VERSION 5.7 ;
BUSBITCHARS "[]" ;
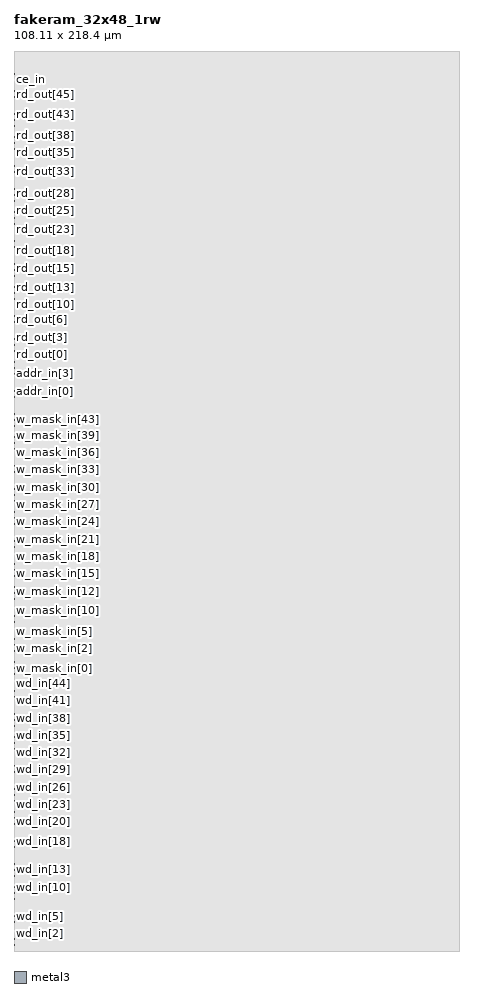
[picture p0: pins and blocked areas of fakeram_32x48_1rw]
MACRO fakeram_32x48_1rw
  FOREIGN fakeram_32x48_1rw 0 0 ;
  SYMMETRY X Y R90 ;
  SIZE 108.110 BY 218.400 ;
  CLASS BLOCK ;
  PIN wd_in[0]
    DIRECTION INPUT ;
    USE SIGNAL ;
    SHAPE ABUTMENT ;
    PORT
      LAYER metal3 ;
      RECT 0.000 1.400 0.140 1.540 ;
    END
  END wd_in[0]
  PIN wd_in[1]
    DIRECTION INPUT ;
    USE SIGNAL ;
    SHAPE ABUTMENT ;
    PORT
      LAYER metal3 ;
      RECT 0.000 2.800 0.140 2.940 ;
    END
  END wd_in[1]
  PIN wd_in[2]
    DIRECTION INPUT ;
    USE SIGNAL ;
    SHAPE ABUTMENT ;
    PORT
      LAYER metal3 ;
      RECT 0.000 4.200 0.140 4.340 ;
    END
  END wd_in[2]
  PIN wd_in[3]
    DIRECTION INPUT ;
    USE SIGNAL ;
    SHAPE ABUTMENT ;
    PORT
      LAYER metal3 ;
      RECT 0.000 5.600 0.140 5.740 ;
    END
  END wd_in[3]
  PIN wd_in[4]
    DIRECTION INPUT ;
    USE SIGNAL ;
    SHAPE ABUTMENT ;
    PORT
      LAYER metal3 ;
      RECT 0.000 7.000 0.140 7.140 ;
    END
  END wd_in[4]
  PIN wd_in[5]
    DIRECTION INPUT ;
    USE SIGNAL ;
    SHAPE ABUTMENT ;
    PORT
      LAYER metal3 ;
      RECT 0.000 8.400 0.140 8.540 ;
    END
  END wd_in[5]
  PIN wd_in[6]
    DIRECTION INPUT ;
    USE SIGNAL ;
    SHAPE ABUTMENT ;
    PORT
      LAYER metal3 ;
      RECT 0.000 9.800 0.140 9.940 ;
    END
  END wd_in[6]
  PIN wd_in[7]
    DIRECTION INPUT ;
    USE SIGNAL ;
    SHAPE ABUTMENT ;
    PORT
      LAYER metal3 ;
      RECT 0.000 11.200 0.140 11.340 ;
    END
  END wd_in[7]
  PIN wd_in[8]
    DIRECTION INPUT ;
    USE SIGNAL ;
    SHAPE ABUTMENT ;
    PORT
      LAYER metal3 ;
      RECT 0.000 12.600 0.140 12.740 ;
    END
  END wd_in[8]
  PIN wd_in[9]
    DIRECTION INPUT ;
    USE SIGNAL ;
    SHAPE ABUTMENT ;
    PORT
      LAYER metal3 ;
      RECT 0.000 14.000 0.140 14.140 ;
    END
  END wd_in[9]
  PIN wd_in[10]
    DIRECTION INPUT ;
    USE SIGNAL ;
    SHAPE ABUTMENT ;
    PORT
      LAYER metal3 ;
      RECT 0.000 15.400 0.140 15.540 ;
    END
  END wd_in[10]
  PIN wd_in[11]
    DIRECTION INPUT ;
    USE SIGNAL ;
    SHAPE ABUTMENT ;
    PORT
      LAYER metal3 ;
      RECT 0.000 16.800 0.140 16.940 ;
    END
  END wd_in[11]
  PIN wd_in[12]
    DIRECTION INPUT ;
    USE SIGNAL ;
    SHAPE ABUTMENT ;
    PORT
      LAYER metal3 ;
      RECT 0.000 18.200 0.140 18.340 ;
    END
  END wd_in[12]
  PIN wd_in[13]
    DIRECTION INPUT ;
    USE SIGNAL ;
    SHAPE ABUTMENT ;
    PORT
      LAYER metal3 ;
      RECT 0.000 19.600 0.140 19.740 ;
    END
  END wd_in[13]
  PIN wd_in[14]
    DIRECTION INPUT ;
    USE SIGNAL ;
    SHAPE ABUTMENT ;
    PORT
      LAYER metal3 ;
      RECT 0.000 21.000 0.140 21.140 ;
    END
  END wd_in[14]
  PIN wd_in[15]
    DIRECTION INPUT ;
    USE SIGNAL ;
    SHAPE ABUTMENT ;
    PORT
      LAYER metal3 ;
      RECT 0.000 22.400 0.140 22.540 ;
    END
  END wd_in[15]
  PIN wd_in[16]
    DIRECTION INPUT ;
    USE SIGNAL ;
    SHAPE ABUTMENT ;
    PORT
      LAYER metal3 ;
      RECT 0.000 23.800 0.140 23.940 ;
    END
  END wd_in[16]
  PIN wd_in[17]
    DIRECTION INPUT ;
    USE SIGNAL ;
    SHAPE ABUTMENT ;
    PORT
      LAYER metal3 ;
      RECT 0.000 25.200 0.140 25.340 ;
    END
  END wd_in[17]
  PIN wd_in[18]
    DIRECTION INPUT ;
    USE SIGNAL ;
    SHAPE ABUTMENT ;
    PORT
      LAYER metal3 ;
      RECT 0.000 26.600 0.140 26.740 ;
    END
  END wd_in[18]
  PIN wd_in[19]
    DIRECTION INPUT ;
    USE SIGNAL ;
    SHAPE ABUTMENT ;
    PORT
      LAYER metal3 ;
      RECT 0.000 28.000 0.140 28.140 ;
    END
  END wd_in[19]
  PIN wd_in[20]
    DIRECTION INPUT ;
    USE SIGNAL ;
    SHAPE ABUTMENT ;
    PORT
      LAYER metal3 ;
      RECT 0.000 29.400 0.140 29.540 ;
    END
  END wd_in[20]
  PIN wd_in[21]
    DIRECTION INPUT ;
    USE SIGNAL ;
    SHAPE ABUTMENT ;
    PORT
      LAYER metal3 ;
      RECT 0.000 30.800 0.140 30.940 ;
    END
  END wd_in[21]
  PIN wd_in[22]
    DIRECTION INPUT ;
    USE SIGNAL ;
    SHAPE ABUTMENT ;
    PORT
      LAYER metal3 ;
      RECT 0.000 32.200 0.140 32.340 ;
    END
  END wd_in[22]
  PIN wd_in[23]
    DIRECTION INPUT ;
    USE SIGNAL ;
    SHAPE ABUTMENT ;
    PORT
      LAYER metal3 ;
      RECT 0.000 33.600 0.140 33.740 ;
    END
  END wd_in[23]
  PIN wd_in[24]
    DIRECTION INPUT ;
    USE SIGNAL ;
    SHAPE ABUTMENT ;
    PORT
      LAYER metal3 ;
      RECT 0.000 35.000 0.140 35.140 ;
    END
  END wd_in[24]
  PIN wd_in[25]
    DIRECTION INPUT ;
    USE SIGNAL ;
    SHAPE ABUTMENT ;
    PORT
      LAYER metal3 ;
      RECT 0.000 36.400 0.140 36.540 ;
    END
  END wd_in[25]
  PIN wd_in[26]
    DIRECTION INPUT ;
    USE SIGNAL ;
    SHAPE ABUTMENT ;
    PORT
      LAYER metal3 ;
      RECT 0.000 37.800 0.140 37.940 ;
    END
  END wd_in[26]
  PIN wd_in[27]
    DIRECTION INPUT ;
    USE SIGNAL ;
    SHAPE ABUTMENT ;
    PORT
      LAYER metal3 ;
      RECT 0.000 39.200 0.140 39.340 ;
    END
  END wd_in[27]
  PIN wd_in[28]
    DIRECTION INPUT ;
    USE SIGNAL ;
    SHAPE ABUTMENT ;
    PORT
      LAYER metal3 ;
      RECT 0.000 40.600 0.140 40.740 ;
    END
  END wd_in[28]
  PIN wd_in[29]
    DIRECTION INPUT ;
    USE SIGNAL ;
    SHAPE ABUTMENT ;
    PORT
      LAYER metal3 ;
      RECT 0.000 42.000 0.140 42.140 ;
    END
  END wd_in[29]
  PIN wd_in[30]
    DIRECTION INPUT ;
    USE SIGNAL ;
    SHAPE ABUTMENT ;
    PORT
      LAYER metal3 ;
      RECT 0.000 43.400 0.140 43.540 ;
    END
  END wd_in[30]
  PIN wd_in[31]
    DIRECTION INPUT ;
    USE SIGNAL ;
    SHAPE ABUTMENT ;
    PORT
      LAYER metal3 ;
      RECT 0.000 44.800 0.140 44.940 ;
    END
  END wd_in[31]
  PIN wd_in[32]
    DIRECTION INPUT ;
    USE SIGNAL ;
    SHAPE ABUTMENT ;
    PORT
      LAYER metal3 ;
      RECT 0.000 46.200 0.140 46.340 ;
    END
  END wd_in[32]
  PIN wd_in[33]
    DIRECTION INPUT ;
    USE SIGNAL ;
    SHAPE ABUTMENT ;
    PORT
      LAYER metal3 ;
      RECT 0.000 47.600 0.140 47.740 ;
    END
  END wd_in[33]
  PIN wd_in[34]
    DIRECTION INPUT ;
    USE SIGNAL ;
    SHAPE ABUTMENT ;
    PORT
      LAYER metal3 ;
      RECT 0.000 49.000 0.140 49.140 ;
    END
  END wd_in[34]
  PIN wd_in[35]
    DIRECTION INPUT ;
    USE SIGNAL ;
    SHAPE ABUTMENT ;
    PORT
      LAYER metal3 ;
      RECT 0.000 50.400 0.140 50.540 ;
    END
  END wd_in[35]
  PIN wd_in[36]
    DIRECTION INPUT ;
    USE SIGNAL ;
    SHAPE ABUTMENT ;
    PORT
      LAYER metal3 ;
      RECT 0.000 51.800 0.140 51.940 ;
    END
  END wd_in[36]
  PIN wd_in[37]
    DIRECTION INPUT ;
    USE SIGNAL ;
    SHAPE ABUTMENT ;
    PORT
      LAYER metal3 ;
      RECT 0.000 53.200 0.140 53.340 ;
    END
  END wd_in[37]
  PIN wd_in[38]
    DIRECTION INPUT ;
    USE SIGNAL ;
    SHAPE ABUTMENT ;
    PORT
      LAYER metal3 ;
      RECT 0.000 54.600 0.140 54.740 ;
    END
  END wd_in[38]
  PIN wd_in[39]
    DIRECTION INPUT ;
    USE SIGNAL ;
    SHAPE ABUTMENT ;
    PORT
      LAYER metal3 ;
      RECT 0.000 56.000 0.140 56.140 ;
    END
  END wd_in[39]
  PIN wd_in[40]
    DIRECTION INPUT ;
    USE SIGNAL ;
    SHAPE ABUTMENT ;
    PORT
      LAYER metal3 ;
      RECT 0.000 57.400 0.140 57.540 ;
    END
  END wd_in[40]
  PIN wd_in[41]
    DIRECTION INPUT ;
    USE SIGNAL ;
    SHAPE ABUTMENT ;
    PORT
      LAYER metal3 ;
      RECT 0.000 58.800 0.140 58.940 ;
    END
  END wd_in[41]
  PIN wd_in[42]
    DIRECTION INPUT ;
    USE SIGNAL ;
    SHAPE ABUTMENT ;
    PORT
      LAYER metal3 ;
      RECT 0.000 60.200 0.140 60.340 ;
    END
  END wd_in[42]
  PIN wd_in[43]
    DIRECTION INPUT ;
    USE SIGNAL ;
    SHAPE ABUTMENT ;
    PORT
      LAYER metal3 ;
      RECT 0.000 61.600 0.140 61.740 ;
    END
  END wd_in[43]
  PIN wd_in[44]
    DIRECTION INPUT ;
    USE SIGNAL ;
    SHAPE ABUTMENT ;
    PORT
      LAYER metal3 ;
      RECT 0.000 63.000 0.140 63.140 ;
    END
  END wd_in[44]
  PIN wd_in[45]
    DIRECTION INPUT ;
    USE SIGNAL ;
    SHAPE ABUTMENT ;
    PORT
      LAYER metal3 ;
      RECT 0.000 64.400 0.140 64.540 ;
    END
  END wd_in[45]
  PIN wd_in[46]
    DIRECTION INPUT ;
    USE SIGNAL ;
    SHAPE ABUTMENT ;
    PORT
      LAYER metal3 ;
      RECT 0.000 65.800 0.140 65.940 ;
    END
  END wd_in[46]
  PIN wd_in[47]
    DIRECTION INPUT ;
    USE SIGNAL ;
    SHAPE ABUTMENT ;
    PORT
      LAYER metal3 ;
      RECT 0.000 67.200 0.140 67.340 ;
    END
  END wd_in[47]
  PIN w_mask_in[0]
    DIRECTION INPUT ;
    USE SIGNAL ;
    SHAPE ABUTMENT ;
    PORT
      LAYER metal3 ;
      RECT 0.000 68.600 0.140 68.740 ;
    END
  END w_mask_in[0]
  PIN w_mask_in[1]
    DIRECTION INPUT ;
    USE SIGNAL ;
    SHAPE ABUTMENT ;
    PORT
      LAYER metal3 ;
      RECT 0.000 70.000 0.140 70.140 ;
    END
  END w_mask_in[1]
  PIN w_mask_in[2]
    DIRECTION INPUT ;
    USE SIGNAL ;
    SHAPE ABUTMENT ;
    PORT
      LAYER metal3 ;
      RECT 0.000 71.400 0.140 71.540 ;
    END
  END w_mask_in[2]
  PIN w_mask_in[3]
    DIRECTION INPUT ;
    USE SIGNAL ;
    SHAPE ABUTMENT ;
    PORT
      LAYER metal3 ;
      RECT 0.000 72.800 0.140 72.940 ;
    END
  END w_mask_in[3]
  PIN w_mask_in[4]
    DIRECTION INPUT ;
    USE SIGNAL ;
    SHAPE ABUTMENT ;
    PORT
      LAYER metal3 ;
      RECT 0.000 74.200 0.140 74.340 ;
    END
  END w_mask_in[4]
  PIN w_mask_in[5]
    DIRECTION INPUT ;
    USE SIGNAL ;
    SHAPE ABUTMENT ;
    PORT
      LAYER metal3 ;
      RECT 0.000 75.600 0.140 75.740 ;
    END
  END w_mask_in[5]
  PIN w_mask_in[6]
    DIRECTION INPUT ;
    USE SIGNAL ;
    SHAPE ABUTMENT ;
    PORT
      LAYER metal3 ;
      RECT 0.000 77.000 0.140 77.140 ;
    END
  END w_mask_in[6]
  PIN w_mask_in[7]
    DIRECTION INPUT ;
    USE SIGNAL ;
    SHAPE ABUTMENT ;
    PORT
      LAYER metal3 ;
      RECT 0.000 78.400 0.140 78.540 ;
    END
  END w_mask_in[7]
  PIN w_mask_in[8]
    DIRECTION INPUT ;
    USE SIGNAL ;
    SHAPE ABUTMENT ;
    PORT
      LAYER metal3 ;
      RECT 0.000 79.800 0.140 79.940 ;
    END
  END w_mask_in[8]
  PIN w_mask_in[9]
    DIRECTION INPUT ;
    USE SIGNAL ;
    SHAPE ABUTMENT ;
    PORT
      LAYER metal3 ;
      RECT 0.000 81.200 0.140 81.340 ;
    END
  END w_mask_in[9]
  PIN w_mask_in[10]
    DIRECTION INPUT ;
    USE SIGNAL ;
    SHAPE ABUTMENT ;
    PORT
      LAYER metal3 ;
      RECT 0.000 82.600 0.140 82.740 ;
    END
  END w_mask_in[10]
  PIN w_mask_in[11]
    DIRECTION INPUT ;
    USE SIGNAL ;
    SHAPE ABUTMENT ;
    PORT
      LAYER metal3 ;
      RECT 0.000 84.000 0.140 84.140 ;
    END
  END w_mask_in[11]
  PIN w_mask_in[12]
    DIRECTION INPUT ;
    USE SIGNAL ;
    SHAPE ABUTMENT ;
    PORT
      LAYER metal3 ;
      RECT 0.000 85.400 0.140 85.540 ;
    END
  END w_mask_in[12]
  PIN w_mask_in[13]
    DIRECTION INPUT ;
    USE SIGNAL ;
    SHAPE ABUTMENT ;
    PORT
      LAYER metal3 ;
      RECT 0.000 86.800 0.140 86.940 ;
    END
  END w_mask_in[13]
  PIN w_mask_in[14]
    DIRECTION INPUT ;
    USE SIGNAL ;
    SHAPE ABUTMENT ;
    PORT
      LAYER metal3 ;
      RECT 0.000 88.200 0.140 88.340 ;
    END
  END w_mask_in[14]
  PIN w_mask_in[15]
    DIRECTION INPUT ;
    USE SIGNAL ;
    SHAPE ABUTMENT ;
    PORT
      LAYER metal3 ;
      RECT 0.000 89.600 0.140 89.740 ;
    END
  END w_mask_in[15]
  PIN w_mask_in[16]
    DIRECTION INPUT ;
    USE SIGNAL ;
    SHAPE ABUTMENT ;
    PORT
      LAYER metal3 ;
      RECT 0.000 91.000 0.140 91.140 ;
    END
  END w_mask_in[16]
  PIN w_mask_in[17]
    DIRECTION INPUT ;
    USE SIGNAL ;
    SHAPE ABUTMENT ;
    PORT
      LAYER metal3 ;
      RECT 0.000 92.400 0.140 92.540 ;
    END
  END w_mask_in[17]
  PIN w_mask_in[18]
    DIRECTION INPUT ;
    USE SIGNAL ;
    SHAPE ABUTMENT ;
    PORT
      LAYER metal3 ;
      RECT 0.000 93.800 0.140 93.940 ;
    END
  END w_mask_in[18]
  PIN w_mask_in[19]
    DIRECTION INPUT ;
    USE SIGNAL ;
    SHAPE ABUTMENT ;
    PORT
      LAYER metal3 ;
      RECT 0.000 95.200 0.140 95.340 ;
    END
  END w_mask_in[19]
  PIN w_mask_in[20]
    DIRECTION INPUT ;
    USE SIGNAL ;
    SHAPE ABUTMENT ;
    PORT
      LAYER metal3 ;
      RECT 0.000 96.600 0.140 96.740 ;
    END
  END w_mask_in[20]
  PIN w_mask_in[21]
    DIRECTION INPUT ;
    USE SIGNAL ;
    SHAPE ABUTMENT ;
    PORT
      LAYER metal3 ;
      RECT 0.000 98.000 0.140 98.140 ;
    END
  END w_mask_in[21]
  PIN w_mask_in[22]
    DIRECTION INPUT ;
    USE SIGNAL ;
    SHAPE ABUTMENT ;
    PORT
      LAYER metal3 ;
      RECT 0.000 99.400 0.140 99.540 ;
    END
  END w_mask_in[22]
  PIN w_mask_in[23]
    DIRECTION INPUT ;
    USE SIGNAL ;
    SHAPE ABUTMENT ;
    PORT
      LAYER metal3 ;
      RECT 0.000 100.800 0.140 100.940 ;
    END
  END w_mask_in[23]
  PIN w_mask_in[24]
    DIRECTION INPUT ;
    USE SIGNAL ;
    SHAPE ABUTMENT ;
    PORT
      LAYER metal3 ;
      RECT 0.000 102.200 0.140 102.340 ;
    END
  END w_mask_in[24]
  PIN w_mask_in[25]
    DIRECTION INPUT ;
    USE SIGNAL ;
    SHAPE ABUTMENT ;
    PORT
      LAYER metal3 ;
      RECT 0.000 103.600 0.140 103.740 ;
    END
  END w_mask_in[25]
  PIN w_mask_in[26]
    DIRECTION INPUT ;
    USE SIGNAL ;
    SHAPE ABUTMENT ;
    PORT
      LAYER metal3 ;
      RECT 0.000 105.000 0.140 105.140 ;
    END
  END w_mask_in[26]
  PIN w_mask_in[27]
    DIRECTION INPUT ;
    USE SIGNAL ;
    SHAPE ABUTMENT ;
    PORT
      LAYER metal3 ;
      RECT 0.000 106.400 0.140 106.540 ;
    END
  END w_mask_in[27]
  PIN w_mask_in[28]
    DIRECTION INPUT ;
    USE SIGNAL ;
    SHAPE ABUTMENT ;
    PORT
      LAYER metal3 ;
      RECT 0.000 107.800 0.140 107.940 ;
    END
  END w_mask_in[28]
  PIN w_mask_in[29]
    DIRECTION INPUT ;
    USE SIGNAL ;
    SHAPE ABUTMENT ;
    PORT
      LAYER metal3 ;
      RECT 0.000 109.200 0.140 109.340 ;
    END
  END w_mask_in[29]
  PIN w_mask_in[30]
    DIRECTION INPUT ;
    USE SIGNAL ;
    SHAPE ABUTMENT ;
    PORT
      LAYER metal3 ;
      RECT 0.000 110.600 0.140 110.740 ;
    END
  END w_mask_in[30]
  PIN w_mask_in[31]
    DIRECTION INPUT ;
    USE SIGNAL ;
    SHAPE ABUTMENT ;
    PORT
      LAYER metal3 ;
      RECT 0.000 112.000 0.140 112.140 ;
    END
  END w_mask_in[31]
  PIN w_mask_in[32]
    DIRECTION INPUT ;
    USE SIGNAL ;
    SHAPE ABUTMENT ;
    PORT
      LAYER metal3 ;
      RECT 0.000 113.400 0.140 113.540 ;
    END
  END w_mask_in[32]
  PIN w_mask_in[33]
    DIRECTION INPUT ;
    USE SIGNAL ;
    SHAPE ABUTMENT ;
    PORT
      LAYER metal3 ;
      RECT 0.000 114.800 0.140 114.940 ;
    END
  END w_mask_in[33]
  PIN w_mask_in[34]
    DIRECTION INPUT ;
    USE SIGNAL ;
    SHAPE ABUTMENT ;
    PORT
      LAYER metal3 ;
      RECT 0.000 116.200 0.140 116.340 ;
    END
  END w_mask_in[34]
  PIN w_mask_in[35]
    DIRECTION INPUT ;
    USE SIGNAL ;
    SHAPE ABUTMENT ;
    PORT
      LAYER metal3 ;
      RECT 0.000 117.600 0.140 117.740 ;
    END
  END w_mask_in[35]
  PIN w_mask_in[36]
    DIRECTION INPUT ;
    USE SIGNAL ;
    SHAPE ABUTMENT ;
    PORT
      LAYER metal3 ;
      RECT 0.000 119.000 0.140 119.140 ;
    END
  END w_mask_in[36]
  PIN w_mask_in[37]
    DIRECTION INPUT ;
    USE SIGNAL ;
    SHAPE ABUTMENT ;
    PORT
      LAYER metal3 ;
      RECT 0.000 120.400 0.140 120.540 ;
    END
  END w_mask_in[37]
  PIN w_mask_in[38]
    DIRECTION INPUT ;
    USE SIGNAL ;
    SHAPE ABUTMENT ;
    PORT
      LAYER metal3 ;
      RECT 0.000 121.800 0.140 121.940 ;
    END
  END w_mask_in[38]
  PIN w_mask_in[39]
    DIRECTION INPUT ;
    USE SIGNAL ;
    SHAPE ABUTMENT ;
    PORT
      LAYER metal3 ;
      RECT 0.000 123.200 0.140 123.340 ;
    END
  END w_mask_in[39]
  PIN w_mask_in[40]
    DIRECTION INPUT ;
    USE SIGNAL ;
    SHAPE ABUTMENT ;
    PORT
      LAYER metal3 ;
      RECT 0.000 124.600 0.140 124.740 ;
    END
  END w_mask_in[40]
  PIN w_mask_in[41]
    DIRECTION INPUT ;
    USE SIGNAL ;
    SHAPE ABUTMENT ;
    PORT
      LAYER metal3 ;
      RECT 0.000 126.000 0.140 126.140 ;
    END
  END w_mask_in[41]
  PIN w_mask_in[42]
    DIRECTION INPUT ;
    USE SIGNAL ;
    SHAPE ABUTMENT ;
    PORT
      LAYER metal3 ;
      RECT 0.000 127.400 0.140 127.540 ;
    END
  END w_mask_in[42]
  PIN w_mask_in[43]
    DIRECTION INPUT ;
    USE SIGNAL ;
    SHAPE ABUTMENT ;
    PORT
      LAYER metal3 ;
      RECT 0.000 128.800 0.140 128.940 ;
    END
  END w_mask_in[43]
  PIN w_mask_in[44]
    DIRECTION INPUT ;
    USE SIGNAL ;
    SHAPE ABUTMENT ;
    PORT
      LAYER metal3 ;
      RECT 0.000 130.200 0.140 130.340 ;
    END
  END w_mask_in[44]
  PIN w_mask_in[45]
    DIRECTION INPUT ;
    USE SIGNAL ;
    SHAPE ABUTMENT ;
    PORT
      LAYER metal3 ;
      RECT 0.000 131.600 0.140 131.740 ;
    END
  END w_mask_in[45]
  PIN w_mask_in[46]
    DIRECTION INPUT ;
    USE SIGNAL ;
    SHAPE ABUTMENT ;
    PORT
      LAYER metal3 ;
      RECT 0.000 133.000 0.140 133.140 ;
    END
  END w_mask_in[46]
  PIN w_mask_in[47]
    DIRECTION INPUT ;
    USE SIGNAL ;
    SHAPE ABUTMENT ;
    PORT
      LAYER metal3 ;
      RECT 0.000 134.400 0.140 134.540 ;
    END
  END w_mask_in[47]
  PIN addr_in[0]
    DIRECTION INPUT ;
    USE SIGNAL ;
    SHAPE ABUTMENT ;
    PORT
      LAYER metal3 ;
      RECT 0.000 135.800 0.140 135.940 ;
    END
  END addr_in[0]
  PIN addr_in[1]
    DIRECTION INPUT ;
    USE SIGNAL ;
    SHAPE ABUTMENT ;
    PORT
      LAYER metal3 ;
      RECT 0.000 137.200 0.140 137.340 ;
    END
  END addr_in[1]
  PIN addr_in[2]
    DIRECTION INPUT ;
    USE SIGNAL ;
    SHAPE ABUTMENT ;
    PORT
      LAYER metal3 ;
      RECT 0.000 138.600 0.140 138.740 ;
    END
  END addr_in[2]
  PIN addr_in[3]
    DIRECTION INPUT ;
    USE SIGNAL ;
    SHAPE ABUTMENT ;
    PORT
      LAYER metal3 ;
      RECT 0.000 140.000 0.140 140.140 ;
    END
  END addr_in[3]
  PIN addr_in[4]
    DIRECTION INPUT ;
    USE SIGNAL ;
    SHAPE ABUTMENT ;
    PORT
      LAYER metal3 ;
      RECT 0.000 141.400 0.140 141.540 ;
    END
  END addr_in[4]
  PIN rd_out[0]
    DIRECTION OUTPUT ;
    USE SIGNAL ;
    SHAPE ABUTMENT ;
    PORT
      LAYER metal3 ;
      RECT 0.000 142.800 0.140 142.940 ;
    END
  END rd_out[0]
  PIN rd_out[1]
    DIRECTION OUTPUT ;
    USE SIGNAL ;
    SHAPE ABUTMENT ;
    PORT
      LAYER metal3 ;
      RECT 0.000 144.200 0.140 144.340 ;
    END
  END rd_out[1]
  PIN rd_out[2]
    DIRECTION OUTPUT ;
    USE SIGNAL ;
    SHAPE ABUTMENT ;
    PORT
      LAYER metal3 ;
      RECT 0.000 145.600 0.140 145.740 ;
    END
  END rd_out[2]
  PIN rd_out[3]
    DIRECTION OUTPUT ;
    USE SIGNAL ;
    SHAPE ABUTMENT ;
    PORT
      LAYER metal3 ;
      RECT 0.000 147.000 0.140 147.140 ;
    END
  END rd_out[3]
  PIN rd_out[4]
    DIRECTION OUTPUT ;
    USE SIGNAL ;
    SHAPE ABUTMENT ;
    PORT
      LAYER metal3 ;
      RECT 0.000 148.400 0.140 148.540 ;
    END
  END rd_out[4]
  PIN rd_out[5]
    DIRECTION OUTPUT ;
    USE SIGNAL ;
    SHAPE ABUTMENT ;
    PORT
      LAYER metal3 ;
      RECT 0.000 149.800 0.140 149.940 ;
    END
  END rd_out[5]
  PIN rd_out[6]
    DIRECTION OUTPUT ;
    USE SIGNAL ;
    SHAPE ABUTMENT ;
    PORT
      LAYER metal3 ;
      RECT 0.000 151.200 0.140 151.340 ;
    END
  END rd_out[6]
  PIN rd_out[7]
    DIRECTION OUTPUT ;
    USE SIGNAL ;
    SHAPE ABUTMENT ;
    PORT
      LAYER metal3 ;
      RECT 0.000 152.600 0.140 152.740 ;
    END
  END rd_out[7]
  PIN rd_out[8]
    DIRECTION OUTPUT ;
    USE SIGNAL ;
    SHAPE ABUTMENT ;
    PORT
      LAYER metal3 ;
      RECT 0.000 154.000 0.140 154.140 ;
    END
  END rd_out[8]
  PIN rd_out[9]
    DIRECTION OUTPUT ;
    USE SIGNAL ;
    SHAPE ABUTMENT ;
    PORT
      LAYER metal3 ;
      RECT 0.000 155.400 0.140 155.540 ;
    END
  END rd_out[9]
  PIN rd_out[10]
    DIRECTION OUTPUT ;
    USE SIGNAL ;
    SHAPE ABUTMENT ;
    PORT
      LAYER metal3 ;
      RECT 0.000 156.800 0.140 156.940 ;
    END
  END rd_out[10]
  PIN rd_out[11]
    DIRECTION OUTPUT ;
    USE SIGNAL ;
    SHAPE ABUTMENT ;
    PORT
      LAYER metal3 ;
      RECT 0.000 158.200 0.140 158.340 ;
    END
  END rd_out[11]
  PIN rd_out[12]
    DIRECTION OUTPUT ;
    USE SIGNAL ;
    SHAPE ABUTMENT ;
    PORT
      LAYER metal3 ;
      RECT 0.000 159.600 0.140 159.740 ;
    END
  END rd_out[12]
  PIN rd_out[13]
    DIRECTION OUTPUT ;
    USE SIGNAL ;
    SHAPE ABUTMENT ;
    PORT
      LAYER metal3 ;
      RECT 0.000 161.000 0.140 161.140 ;
    END
  END rd_out[13]
  PIN rd_out[14]
    DIRECTION OUTPUT ;
    USE SIGNAL ;
    SHAPE ABUTMENT ;
    PORT
      LAYER metal3 ;
      RECT 0.000 162.400 0.140 162.540 ;
    END
  END rd_out[14]
  PIN rd_out[15]
    DIRECTION OUTPUT ;
    USE SIGNAL ;
    SHAPE ABUTMENT ;
    PORT
      LAYER metal3 ;
      RECT 0.000 163.800 0.140 163.940 ;
    END
  END rd_out[15]
  PIN rd_out[16]
    DIRECTION OUTPUT ;
    USE SIGNAL ;
    SHAPE ABUTMENT ;
    PORT
      LAYER metal3 ;
      RECT 0.000 165.200 0.140 165.340 ;
    END
  END rd_out[16]
  PIN rd_out[17]
    DIRECTION OUTPUT ;
    USE SIGNAL ;
    SHAPE ABUTMENT ;
    PORT
      LAYER metal3 ;
      RECT 0.000 166.600 0.140 166.740 ;
    END
  END rd_out[17]
  PIN rd_out[18]
    DIRECTION OUTPUT ;
    USE SIGNAL ;
    SHAPE ABUTMENT ;
    PORT
      LAYER metal3 ;
      RECT 0.000 168.000 0.140 168.140 ;
    END
  END rd_out[18]
  PIN rd_out[19]
    DIRECTION OUTPUT ;
    USE SIGNAL ;
    SHAPE ABUTMENT ;
    PORT
      LAYER metal3 ;
      RECT 0.000 169.400 0.140 169.540 ;
    END
  END rd_out[19]
  PIN rd_out[20]
    DIRECTION OUTPUT ;
    USE SIGNAL ;
    SHAPE ABUTMENT ;
    PORT
      LAYER metal3 ;
      RECT 0.000 170.800 0.140 170.940 ;
    END
  END rd_out[20]
  PIN rd_out[21]
    DIRECTION OUTPUT ;
    USE SIGNAL ;
    SHAPE ABUTMENT ;
    PORT
      LAYER metal3 ;
      RECT 0.000 172.200 0.140 172.340 ;
    END
  END rd_out[21]
  PIN rd_out[22]
    DIRECTION OUTPUT ;
    USE SIGNAL ;
    SHAPE ABUTMENT ;
    PORT
      LAYER metal3 ;
      RECT 0.000 173.600 0.140 173.740 ;
    END
  END rd_out[22]
  PIN rd_out[23]
    DIRECTION OUTPUT ;
    USE SIGNAL ;
    SHAPE ABUTMENT ;
    PORT
      LAYER metal3 ;
      RECT 0.000 175.000 0.140 175.140 ;
    END
  END rd_out[23]
  PIN rd_out[24]
    DIRECTION OUTPUT ;
    USE SIGNAL ;
    SHAPE ABUTMENT ;
    PORT
      LAYER metal3 ;
      RECT 0.000 176.400 0.140 176.540 ;
    END
  END rd_out[24]
  PIN rd_out[25]
    DIRECTION OUTPUT ;
    USE SIGNAL ;
    SHAPE ABUTMENT ;
    PORT
      LAYER metal3 ;
      RECT 0.000 177.800 0.140 177.940 ;
    END
  END rd_out[25]
  PIN rd_out[26]
    DIRECTION OUTPUT ;
    USE SIGNAL ;
    SHAPE ABUTMENT ;
    PORT
      LAYER metal3 ;
      RECT 0.000 179.200 0.140 179.340 ;
    END
  END rd_out[26]
  PIN rd_out[27]
    DIRECTION OUTPUT ;
    USE SIGNAL ;
    SHAPE ABUTMENT ;
    PORT
      LAYER metal3 ;
      RECT 0.000 180.600 0.140 180.740 ;
    END
  END rd_out[27]
  PIN rd_out[28]
    DIRECTION OUTPUT ;
    USE SIGNAL ;
    SHAPE ABUTMENT ;
    PORT
      LAYER metal3 ;
      RECT 0.000 182.000 0.140 182.140 ;
    END
  END rd_out[28]
  PIN rd_out[29]
    DIRECTION OUTPUT ;
    USE SIGNAL ;
    SHAPE ABUTMENT ;
    PORT
      LAYER metal3 ;
      RECT 0.000 183.400 0.140 183.540 ;
    END
  END rd_out[29]
  PIN rd_out[30]
    DIRECTION OUTPUT ;
    USE SIGNAL ;
    SHAPE ABUTMENT ;
    PORT
      LAYER metal3 ;
      RECT 0.000 184.800 0.140 184.940 ;
    END
  END rd_out[30]
  PIN rd_out[31]
    DIRECTION OUTPUT ;
    USE SIGNAL ;
    SHAPE ABUTMENT ;
    PORT
      LAYER metal3 ;
      RECT 0.000 186.200 0.140 186.340 ;
    END
  END rd_out[31]
  PIN rd_out[32]
    DIRECTION OUTPUT ;
    USE SIGNAL ;
    SHAPE ABUTMENT ;
    PORT
      LAYER metal3 ;
      RECT 0.000 187.600 0.140 187.740 ;
    END
  END rd_out[32]
  PIN rd_out[33]
    DIRECTION OUTPUT ;
    USE SIGNAL ;
    SHAPE ABUTMENT ;
    PORT
      LAYER metal3 ;
      RECT 0.000 189.000 0.140 189.140 ;
    END
  END rd_out[33]
  PIN rd_out[34]
    DIRECTION OUTPUT ;
    USE SIGNAL ;
    SHAPE ABUTMENT ;
    PORT
      LAYER metal3 ;
      RECT 0.000 190.400 0.140 190.540 ;
    END
  END rd_out[34]
  PIN rd_out[35]
    DIRECTION OUTPUT ;
    USE SIGNAL ;
    SHAPE ABUTMENT ;
    PORT
      LAYER metal3 ;
      RECT 0.000 191.800 0.140 191.940 ;
    END
  END rd_out[35]
  PIN rd_out[36]
    DIRECTION OUTPUT ;
    USE SIGNAL ;
    SHAPE ABUTMENT ;
    PORT
      LAYER metal3 ;
      RECT 0.000 193.200 0.140 193.340 ;
    END
  END rd_out[36]
  PIN rd_out[37]
    DIRECTION OUTPUT ;
    USE SIGNAL ;
    SHAPE ABUTMENT ;
    PORT
      LAYER metal3 ;
      RECT 0.000 194.600 0.140 194.740 ;
    END
  END rd_out[37]
  PIN rd_out[38]
    DIRECTION OUTPUT ;
    USE SIGNAL ;
    SHAPE ABUTMENT ;
    PORT
      LAYER metal3 ;
      RECT 0.000 196.000 0.140 196.140 ;
    END
  END rd_out[38]
  PIN rd_out[39]
    DIRECTION OUTPUT ;
    USE SIGNAL ;
    SHAPE ABUTMENT ;
    PORT
      LAYER metal3 ;
      RECT 0.000 197.400 0.140 197.540 ;
    END
  END rd_out[39]
  PIN rd_out[40]
    DIRECTION OUTPUT ;
    USE SIGNAL ;
    SHAPE ABUTMENT ;
    PORT
      LAYER metal3 ;
      RECT 0.000 198.800 0.140 198.940 ;
    END
  END rd_out[40]
  PIN rd_out[41]
    DIRECTION OUTPUT ;
    USE SIGNAL ;
    SHAPE ABUTMENT ;
    PORT
      LAYER metal3 ;
      RECT 0.000 200.200 0.140 200.340 ;
    END
  END rd_out[41]
  PIN rd_out[42]
    DIRECTION OUTPUT ;
    USE SIGNAL ;
    SHAPE ABUTMENT ;
    PORT
      LAYER metal3 ;
      RECT 0.000 201.600 0.140 201.740 ;
    END
  END rd_out[42]
  PIN rd_out[43]
    DIRECTION OUTPUT ;
    USE SIGNAL ;
    SHAPE ABUTMENT ;
    PORT
      LAYER metal3 ;
      RECT 0.000 203.000 0.140 203.140 ;
    END
  END rd_out[43]
  PIN rd_out[44]
    DIRECTION OUTPUT ;
    USE SIGNAL ;
    SHAPE ABUTMENT ;
    PORT
      LAYER metal3 ;
      RECT 0.000 204.400 0.140 204.540 ;
    END
  END rd_out[44]
  PIN rd_out[45]
    DIRECTION OUTPUT ;
    USE SIGNAL ;
    SHAPE ABUTMENT ;
    PORT
      LAYER metal3 ;
      RECT 0.000 205.800 0.140 205.940 ;
    END
  END rd_out[45]
  PIN rd_out[46]
    DIRECTION OUTPUT ;
    USE SIGNAL ;
    SHAPE ABUTMENT ;
    PORT
      LAYER metal3 ;
      RECT 0.000 207.200 0.140 207.340 ;
    END
  END rd_out[46]
  PIN rd_out[47]
    DIRECTION OUTPUT ;
    USE SIGNAL ;
    SHAPE ABUTMENT ;
    PORT
      LAYER metal3 ;
      RECT 0.000 208.600 0.140 208.740 ;
    END
  END rd_out[47]
  PIN clk
    DIRECTION INPUT ;
    USE SIGNAL ;
    SHAPE ABUTMENT ;
    PORT
      LAYER metal3 ;
      RECT 0.000 210.000 0.140 210.140 ;
    END
  END clk
  PIN ce_in
    DIRECTION INPUT ;
    USE SIGNAL ;
    SHAPE ABUTMENT ;
    PORT
      LAYER metal3 ;
      RECT 0.000 211.400 0.140 211.540 ;
    END
  END ce_in
  PIN we_in
    DIRECTION INPUT ;
    USE SIGNAL ;
    SHAPE ABUTMENT ;
    PORT
      LAYER metal3 ;
      RECT 0.000 212.800 0.140 212.940 ;
    END
  END we_in
  OBS
    LAYER metal1 ;
      RECT 0.000 0.000 108.110 218.400 ;
    LAYER metal2 ;
      RECT 0.000 0.000 108.110 218.400 ;
    LAYER metal3 ;
      RECT 0.000 0.000 108.110 218.400 ;
    LAYER metal4 ;
      RECT 0.000 0.000 108.110 218.400 ;
  END
END fakeram_32x48_1rw
END LIBRARY
